VERSION 5.8 ;
BUSBITCHARS "[]" ;
DIVIDERCHAR "/" ;
UNITS
    DATABASE MICRONS 1000 ;
END UNITS

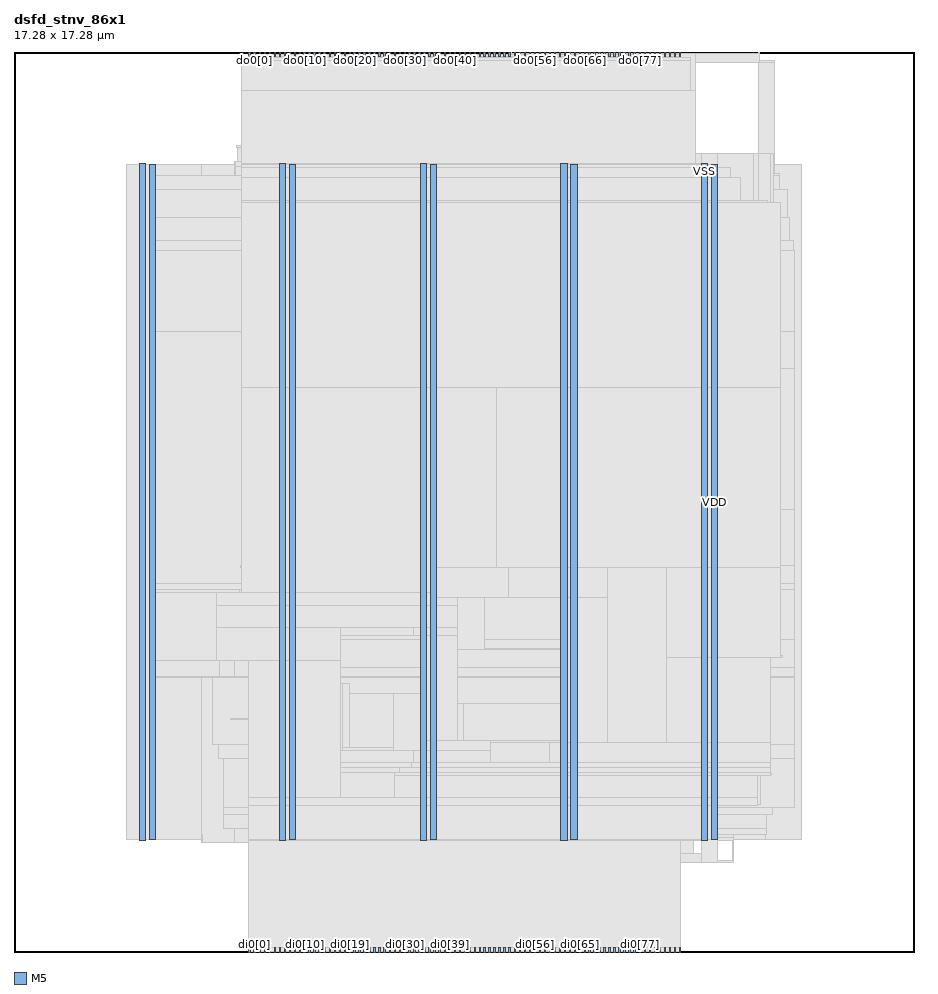
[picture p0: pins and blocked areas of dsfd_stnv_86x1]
MACRO dsfd_stnv_86x1
  FOREIGN dsfd_stnv_86x1 0 0 ;
  CLASS BLOCK ;
  SIZE 17.28 BY 17.28 ;
  PIN di0[0]
    DIRECTION INPUT ;
    USE SIGNAL ;
    PORT
      LAYER M5 ;
        RECT  4.608 0 4.632 0.084 ;
    END
  END di0[0]
  PIN di0[10]
    DIRECTION INPUT ;
    USE SIGNAL ;
    PORT
      LAYER M5 ;
        RECT  5.568 0 5.592 0.084 ;
    END
  END di0[10]
  PIN di0[11]
    DIRECTION INPUT ;
    USE SIGNAL ;
    PORT
      LAYER M5 ;
        RECT  5.664 0 5.688 0.084 ;
    END
  END di0[11]
  PIN di0[12]
    DIRECTION INPUT ;
    USE SIGNAL ;
    PORT
      LAYER M5 ;
        RECT  5.76 0 5.784 0.084 ;
    END
  END di0[12]
  PIN di0[13]
    DIRECTION INPUT ;
    USE SIGNAL ;
    PORT
      LAYER M5 ;
        RECT  5.856 0 5.88 0.084 ;
    END
  END di0[13]
  PIN di0[14]
    DIRECTION INPUT ;
    USE SIGNAL ;
    PORT
      LAYER M5 ;
        RECT  5.952 0 5.976 0.084 ;
    END
  END di0[14]
  PIN di0[15]
    DIRECTION INPUT ;
    USE SIGNAL ;
    PORT
      LAYER M5 ;
        RECT  6.048 0 6.072 0.084 ;
    END
  END di0[15]
  PIN di0[16]
    DIRECTION INPUT ;
    USE SIGNAL ;
    PORT
      LAYER M5 ;
        RECT  6.144 0 6.168 0.084 ;
    END
  END di0[16]
  PIN di0[17]
    DIRECTION INPUT ;
    USE SIGNAL ;
    PORT
      LAYER M5 ;
        RECT  6.24 0 6.264 0.084 ;
    END
  END di0[17]
  PIN di0[18]
    DIRECTION INPUT ;
    USE SIGNAL ;
    PORT
      LAYER M5 ;
        RECT  6.336 0 6.36 0.084 ;
    END
  END di0[18]
  PIN di0[19]
    DIRECTION INPUT ;
    USE SIGNAL ;
    PORT
      LAYER M5 ;
        RECT  6.432 0 6.456 0.084 ;
    END
  END di0[19]
  PIN di0[1]
    DIRECTION INPUT ;
    USE SIGNAL ;
    PORT
      LAYER M5 ;
        RECT  4.704 0 4.728 0.084 ;
    END
  END di0[1]
  PIN di0[20]
    DIRECTION INPUT ;
    USE SIGNAL ;
    PORT
      LAYER M5 ;
        RECT  6.528 0 6.552 0.084 ;
    END
  END di0[20]
  PIN di0[21]
    DIRECTION INPUT ;
    USE SIGNAL ;
    PORT
      LAYER M5 ;
        RECT  6.624 0 6.648 0.084 ;
    END
  END di0[21]
  PIN di0[22]
    DIRECTION INPUT ;
    USE SIGNAL ;
    PORT
      LAYER M5 ;
        RECT  6.72 0 6.744 0.084 ;
    END
  END di0[22]
  PIN di0[23]
    DIRECTION INPUT ;
    USE SIGNAL ;
    PORT
      LAYER M5 ;
        RECT  6.816 0 6.84 0.084 ;
    END
  END di0[23]
  PIN di0[24]
    DIRECTION INPUT ;
    USE SIGNAL ;
    PORT
      LAYER M5 ;
        RECT  6.912 0 6.936 0.084 ;
    END
  END di0[24]
  PIN di0[25]
    DIRECTION INPUT ;
    USE SIGNAL ;
    PORT
      LAYER M5 ;
        RECT  7.008 0 7.032 0.084 ;
    END
  END di0[25]
  PIN di0[26]
    DIRECTION INPUT ;
    USE SIGNAL ;
    PORT
      LAYER M5 ;
        RECT  7.104 0 7.128 0.084 ;
    END
  END di0[26]
  PIN di0[27]
    DIRECTION INPUT ;
    USE SIGNAL ;
    PORT
      LAYER M5 ;
        RECT  7.2 0 7.224 0.084 ;
    END
  END di0[27]
  PIN di0[28]
    DIRECTION INPUT ;
    USE SIGNAL ;
    PORT
      LAYER M5 ;
        RECT  7.296 0 7.32 0.084 ;
    END
  END di0[28]
  PIN di0[29]
    DIRECTION INPUT ;
    USE SIGNAL ;
    PORT
      LAYER M5 ;
        RECT  7.392 0 7.416 0.084 ;
    END
  END di0[29]
  PIN di0[2]
    DIRECTION INPUT ;
    USE SIGNAL ;
    PORT
      LAYER M5 ;
        RECT  4.8 0 4.824 0.084 ;
    END
  END di0[2]
  PIN di0[30]
    DIRECTION INPUT ;
    USE SIGNAL ;
    PORT
      LAYER M5 ;
        RECT  7.488 0 7.512 0.084 ;
    END
  END di0[30]
  PIN di0[31]
    DIRECTION INPUT ;
    USE SIGNAL ;
    PORT
      LAYER M5 ;
        RECT  7.584 0 7.608 0.084 ;
    END
  END di0[31]
  PIN di0[32]
    DIRECTION INPUT ;
    USE SIGNAL ;
    PORT
      LAYER M5 ;
        RECT  7.68 0 7.704 0.084 ;
    END
  END di0[32]
  PIN di0[33]
    DIRECTION INPUT ;
    USE SIGNAL ;
    PORT
      LAYER M5 ;
        RECT  7.776 0 7.8 0.084 ;
    END
  END di0[33]
  PIN di0[34]
    DIRECTION INPUT ;
    USE SIGNAL ;
    PORT
      LAYER M5 ;
        RECT  7.872 0 7.896 0.084 ;
    END
  END di0[34]
  PIN di0[35]
    DIRECTION INPUT ;
    USE SIGNAL ;
    PORT
      LAYER M5 ;
        RECT  7.968 0 7.992 0.084 ;
    END
  END di0[35]
  PIN di0[36]
    DIRECTION INPUT ;
    USE SIGNAL ;
    PORT
      LAYER M5 ;
        RECT  8.064 0 8.088 0.084 ;
    END
  END di0[36]
  PIN di0[37]
    DIRECTION INPUT ;
    USE SIGNAL ;
    PORT
      LAYER M5 ;
        RECT  8.16 0 8.184 0.084 ;
    END
  END di0[37]
  PIN di0[38]
    DIRECTION INPUT ;
    USE SIGNAL ;
    PORT
      LAYER M5 ;
        RECT  8.256 0 8.28 0.084 ;
    END
  END di0[38]
  PIN di0[39]
    DIRECTION INPUT ;
    USE SIGNAL ;
    PORT
      LAYER M5 ;
        RECT  8.352 0 8.376 0.084 ;
    END
  END di0[39]
  PIN di0[3]
    DIRECTION INPUT ;
    USE SIGNAL ;
    PORT
      LAYER M5 ;
        RECT  4.896 0 4.92 0.084 ;
    END
  END di0[3]
  PIN di0[40]
    DIRECTION INPUT ;
    USE SIGNAL ;
    PORT
      LAYER M5 ;
        RECT  8.448 0 8.472 0.084 ;
    END
  END di0[40]
  PIN di0[41]
    DIRECTION INPUT ;
    USE SIGNAL ;
    PORT
      LAYER M5 ;
        RECT  8.544 0 8.568 0.084 ;
    END
  END di0[41]
  PIN di0[42]
    DIRECTION INPUT ;
    USE SIGNAL ;
    PORT
      LAYER M5 ;
        RECT  8.64 0 8.664 0.084 ;
    END
  END di0[42]
  PIN di0[43]
    DIRECTION INPUT ;
    USE SIGNAL ;
    PORT
      LAYER M5 ;
        RECT  8.736 0 8.76 0.084 ;
    END
  END di0[43]
  PIN di0[44]
    DIRECTION INPUT ;
    USE SIGNAL ;
    PORT
      LAYER M5 ;
        RECT  8.832 0 8.856 0.084 ;
    END
  END di0[44]
  PIN di0[45]
    DIRECTION INPUT ;
    USE SIGNAL ;
    PORT
      LAYER M5 ;
        RECT  8.928 0 8.952 0.084 ;
    END
  END di0[45]
  PIN di0[46]
    DIRECTION INPUT ;
    USE SIGNAL ;
    PORT
      LAYER M5 ;
        RECT  9.024 0 9.048 0.084 ;
    END
  END di0[46]
  PIN di0[47]
    DIRECTION INPUT ;
    USE SIGNAL ;
    PORT
      LAYER M5 ;
        RECT  9.12 0 9.144 0.084 ;
    END
  END di0[47]
  PIN di0[48]
    DIRECTION INPUT ;
    USE SIGNAL ;
    PORT
      LAYER M5 ;
        RECT  9.216 0 9.24 0.084 ;
    END
  END di0[48]
  PIN di0[49]
    DIRECTION INPUT ;
    USE SIGNAL ;
    PORT
      LAYER M5 ;
        RECT  9.312 0 9.336 0.084 ;
    END
  END di0[49]
  PIN di0[4]
    DIRECTION INPUT ;
    USE SIGNAL ;
    PORT
      LAYER M5 ;
        RECT  4.992 0 5.016 0.084 ;
    END
  END di0[4]
  PIN di0[50]
    DIRECTION INPUT ;
    USE SIGNAL ;
    PORT
      LAYER M5 ;
        RECT  9.408 0 9.432 0.084 ;
    END
  END di0[50]
  PIN di0[51]
    DIRECTION INPUT ;
    USE SIGNAL ;
    PORT
      LAYER M5 ;
        RECT  9.504 0 9.528 0.084 ;
    END
  END di0[51]
  PIN di0[52]
    DIRECTION INPUT ;
    USE SIGNAL ;
    PORT
      LAYER M5 ;
        RECT  9.6 0 9.624 0.084 ;
    END
  END di0[52]
  PIN di0[53]
    DIRECTION INPUT ;
    USE SIGNAL ;
    PORT
      LAYER M5 ;
        RECT  9.696 0 9.72 0.084 ;
    END
  END di0[53]
  PIN di0[54]
    DIRECTION INPUT ;
    USE SIGNAL ;
    PORT
      LAYER M5 ;
        RECT  9.792 0 9.816 0.084 ;
    END
  END di0[54]
  PIN di0[55]
    DIRECTION INPUT ;
    USE SIGNAL ;
    PORT
      LAYER M5 ;
        RECT  9.888 0 9.912 0.084 ;
    END
  END di0[55]
  PIN di0[56]
    DIRECTION INPUT ;
    USE SIGNAL ;
    PORT
      LAYER M5 ;
        RECT  9.984 0 10.008 0.084 ;
    END
  END di0[56]
  PIN di0[57]
    DIRECTION INPUT ;
    USE SIGNAL ;
    PORT
      LAYER M5 ;
        RECT  10.08 0 10.104 0.084 ;
    END
  END di0[57]
  PIN di0[58]
    DIRECTION INPUT ;
    USE SIGNAL ;
    PORT
      LAYER M5 ;
        RECT  10.176 0 10.2 0.084 ;
    END
  END di0[58]
  PIN di0[59]
    DIRECTION INPUT ;
    USE SIGNAL ;
    PORT
      LAYER M5 ;
        RECT  10.272 0 10.296 0.084 ;
    END
  END di0[59]
  PIN di0[5]
    DIRECTION INPUT ;
    USE SIGNAL ;
    PORT
      LAYER M5 ;
        RECT  5.088 0 5.112 0.084 ;
    END
  END di0[5]
  PIN di0[60]
    DIRECTION INPUT ;
    USE SIGNAL ;
    PORT
      LAYER M5 ;
        RECT  10.368 0 10.392 0.084 ;
    END
  END di0[60]
  PIN di0[61]
    DIRECTION INPUT ;
    USE SIGNAL ;
    PORT
      LAYER M5 ;
        RECT  10.464 0 10.488 0.084 ;
    END
  END di0[61]
  PIN di0[62]
    DIRECTION INPUT ;
    USE SIGNAL ;
    PORT
      LAYER M5 ;
        RECT  10.56 0 10.584 0.084 ;
    END
  END di0[62]
  PIN di0[63]
    DIRECTION INPUT ;
    USE SIGNAL ;
    PORT
      LAYER M5 ;
        RECT  10.656 0 10.68 0.084 ;
    END
  END di0[63]
  PIN di0[64]
    DIRECTION INPUT ;
    USE SIGNAL ;
    PORT
      LAYER M5 ;
        RECT  10.752 0 10.776 0.084 ;
    END
  END di0[64]
  PIN di0[65]
    DIRECTION INPUT ;
    USE SIGNAL ;
    PORT
      LAYER M5 ;
        RECT  10.848 0 10.872 0.084 ;
    END
  END di0[65]
  PIN di0[66]
    DIRECTION INPUT ;
    USE SIGNAL ;
    PORT
      LAYER M5 ;
        RECT  10.944 0 10.968 0.084 ;
    END
  END di0[66]
  PIN di0[67]
    DIRECTION INPUT ;
    USE SIGNAL ;
    PORT
      LAYER M5 ;
        RECT  11.04 0 11.064 0.084 ;
    END
  END di0[67]
  PIN di0[68]
    DIRECTION INPUT ;
    USE SIGNAL ;
    PORT
      LAYER M5 ;
        RECT  11.136 0 11.16 0.084 ;
    END
  END di0[68]
  PIN di0[69]
    DIRECTION INPUT ;
    USE SIGNAL ;
    PORT
      LAYER M5 ;
        RECT  11.232 0 11.256 0.084 ;
    END
  END di0[69]
  PIN di0[6]
    DIRECTION INPUT ;
    USE SIGNAL ;
    PORT
      LAYER M5 ;
        RECT  5.184 0 5.208 0.084 ;
    END
  END di0[6]
  PIN di0[70]
    DIRECTION INPUT ;
    USE SIGNAL ;
    PORT
      LAYER M5 ;
        RECT  11.328 0 11.352 0.084 ;
    END
  END di0[70]
  PIN di0[71]
    DIRECTION INPUT ;
    USE SIGNAL ;
    PORT
      LAYER M5 ;
        RECT  11.424 0 11.448 0.084 ;
    END
  END di0[71]
  PIN di0[72]
    DIRECTION INPUT ;
    USE SIGNAL ;
    PORT
      LAYER M5 ;
        RECT  11.52 0 11.544 0.084 ;
    END
  END di0[72]
  PIN di0[73]
    DIRECTION INPUT ;
    USE SIGNAL ;
    PORT
      LAYER M5 ;
        RECT  11.616 0 11.64 0.084 ;
    END
  END di0[73]
  PIN di0[74]
    DIRECTION INPUT ;
    USE SIGNAL ;
    PORT
      LAYER M5 ;
        RECT  11.712 0 11.736 0.084 ;
    END
  END di0[74]
  PIN di0[75]
    DIRECTION INPUT ;
    USE SIGNAL ;
    PORT
      LAYER M5 ;
        RECT  11.808 0 11.832 0.084 ;
    END
  END di0[75]
  PIN di0[76]
    DIRECTION INPUT ;
    USE SIGNAL ;
    PORT
      LAYER M5 ;
        RECT  11.904 0 11.928 0.084 ;
    END
  END di0[76]
  PIN di0[77]
    DIRECTION INPUT ;
    USE SIGNAL ;
    PORT
      LAYER M5 ;
        RECT  12 0 12.024 0.084 ;
    END
  END di0[77]
  PIN di0[78]
    DIRECTION INPUT ;
    USE SIGNAL ;
    PORT
      LAYER M5 ;
        RECT  12.096 0 12.12 0.084 ;
    END
  END di0[78]
  PIN di0[79]
    DIRECTION INPUT ;
    USE SIGNAL ;
    PORT
      LAYER M5 ;
        RECT  12.192 0 12.216 0.084 ;
    END
  END di0[79]
  PIN di0[7]
    DIRECTION INPUT ;
    USE SIGNAL ;
    PORT
      LAYER M5 ;
        RECT  5.28 0 5.304 0.084 ;
    END
  END di0[7]
  PIN di0[80]
    DIRECTION INPUT ;
    USE SIGNAL ;
    PORT
      LAYER M5 ;
        RECT  12.288 0 12.312 0.084 ;
    END
  END di0[80]
  PIN di0[81]
    DIRECTION INPUT ;
    USE SIGNAL ;
    PORT
      LAYER M5 ;
        RECT  12.384 0 12.408 0.084 ;
    END
  END di0[81]
  PIN di0[82]
    DIRECTION INPUT ;
    USE SIGNAL ;
    PORT
      LAYER M5 ;
        RECT  12.48 0 12.504 0.084 ;
    END
  END di0[82]
  PIN di0[83]
    DIRECTION INPUT ;
    USE SIGNAL ;
    PORT
      LAYER M5 ;
        RECT  12.576 0 12.6 0.084 ;
    END
  END di0[83]
  PIN di0[84]
    DIRECTION INPUT ;
    USE SIGNAL ;
    PORT
      LAYER M5 ;
        RECT  12.672 0 12.696 0.084 ;
    END
  END di0[84]
  PIN di0[85]
    DIRECTION INPUT ;
    USE SIGNAL ;
    PORT
      LAYER M5 ;
        RECT  12.768 0 12.792 0.084 ;
    END
  END di0[85]
  PIN di0[8]
    DIRECTION INPUT ;
    USE SIGNAL ;
    PORT
      LAYER M5 ;
        RECT  5.376 0 5.4 0.084 ;
    END
  END di0[8]
  PIN di0[9]
    DIRECTION INPUT ;
    USE SIGNAL ;
    PORT
      LAYER M5 ;
        RECT  5.472 0 5.496 0.084 ;
    END
  END di0[9]
  PIN do0[0]
    DIRECTION OUTPUT ;
    USE SIGNAL ;
    PORT
      LAYER M5 ;
        RECT  4.608 17.196 4.632 17.28 ;
    END
  END do0[0]
  PIN do0[10]
    DIRECTION OUTPUT ;
    USE SIGNAL ;
    PORT
      LAYER M5 ;
        RECT  5.568 17.196 5.592 17.28 ;
    END
  END do0[10]
  PIN do0[11]
    DIRECTION OUTPUT ;
    USE SIGNAL ;
    PORT
      LAYER M5 ;
        RECT  5.664 17.196 5.688 17.28 ;
    END
  END do0[11]
  PIN do0[12]
    DIRECTION OUTPUT ;
    USE SIGNAL ;
    PORT
      LAYER M5 ;
        RECT  5.76 17.196 5.784 17.28 ;
    END
  END do0[12]
  PIN do0[13]
    DIRECTION OUTPUT ;
    USE SIGNAL ;
    PORT
      LAYER M5 ;
        RECT  5.856 17.196 5.88 17.28 ;
    END
  END do0[13]
  PIN do0[14]
    DIRECTION OUTPUT ;
    USE SIGNAL ;
    PORT
      LAYER M5 ;
        RECT  5.952 17.196 5.976 17.28 ;
    END
  END do0[14]
  PIN do0[15]
    DIRECTION OUTPUT ;
    USE SIGNAL ;
    PORT
      LAYER M5 ;
        RECT  6.048 17.196 6.072 17.28 ;
    END
  END do0[15]
  PIN do0[16]
    DIRECTION OUTPUT ;
    USE SIGNAL ;
    PORT
      LAYER M5 ;
        RECT  6.144 17.196 6.168 17.28 ;
    END
  END do0[16]
  PIN do0[17]
    DIRECTION OUTPUT ;
    USE SIGNAL ;
    PORT
      LAYER M5 ;
        RECT  6.24 17.196 6.264 17.28 ;
    END
  END do0[17]
  PIN do0[18]
    DIRECTION OUTPUT ;
    USE SIGNAL ;
    PORT
      LAYER M5 ;
        RECT  6.336 17.196 6.36 17.28 ;
    END
  END do0[18]
  PIN do0[19]
    DIRECTION OUTPUT ;
    USE SIGNAL ;
    PORT
      LAYER M5 ;
        RECT  6.432 17.196 6.456 17.28 ;
    END
  END do0[19]
  PIN do0[1]
    DIRECTION OUTPUT ;
    USE SIGNAL ;
    PORT
      LAYER M5 ;
        RECT  4.704 17.196 4.728 17.28 ;
    END
  END do0[1]
  PIN do0[20]
    DIRECTION OUTPUT ;
    USE SIGNAL ;
    PORT
      LAYER M5 ;
        RECT  6.528 17.196 6.552 17.28 ;
    END
  END do0[20]
  PIN do0[21]
    DIRECTION OUTPUT ;
    USE SIGNAL ;
    PORT
      LAYER M5 ;
        RECT  6.624 17.196 6.648 17.28 ;
    END
  END do0[21]
  PIN do0[22]
    DIRECTION OUTPUT ;
    USE SIGNAL ;
    PORT
      LAYER M5 ;
        RECT  6.72 17.196 6.744 17.28 ;
    END
  END do0[22]
  PIN do0[23]
    DIRECTION OUTPUT ;
    USE SIGNAL ;
    PORT
      LAYER M5 ;
        RECT  6.816 17.196 6.84 17.28 ;
    END
  END do0[23]
  PIN do0[24]
    DIRECTION OUTPUT ;
    USE SIGNAL ;
    PORT
      LAYER M5 ;
        RECT  6.912 17.196 6.936 17.28 ;
    END
  END do0[24]
  PIN do0[25]
    DIRECTION OUTPUT ;
    USE SIGNAL ;
    PORT
      LAYER M5 ;
        RECT  7.008 17.196 7.032 17.28 ;
    END
  END do0[25]
  PIN do0[26]
    DIRECTION OUTPUT ;
    USE SIGNAL ;
    PORT
      LAYER M5 ;
        RECT  7.104 17.196 7.128 17.28 ;
    END
  END do0[26]
  PIN do0[27]
    DIRECTION OUTPUT ;
    USE SIGNAL ;
    PORT
      LAYER M5 ;
        RECT  7.2 17.196 7.224 17.28 ;
    END
  END do0[27]
  PIN do0[28]
    DIRECTION OUTPUT ;
    USE SIGNAL ;
    PORT
      LAYER M5 ;
        RECT  7.296 17.196 7.32 17.28 ;
    END
  END do0[28]
  PIN do0[29]
    DIRECTION OUTPUT ;
    USE SIGNAL ;
    PORT
      LAYER M5 ;
        RECT  7.392 17.196 7.416 17.28 ;
    END
  END do0[29]
  PIN do0[2]
    DIRECTION OUTPUT ;
    USE SIGNAL ;
    PORT
      LAYER M5 ;
        RECT  4.8 17.196 4.824 17.28 ;
    END
  END do0[2]
  PIN do0[30]
    DIRECTION OUTPUT ;
    USE SIGNAL ;
    PORT
      LAYER M5 ;
        RECT  7.488 17.196 7.512 17.28 ;
    END
  END do0[30]
  PIN do0[31]
    DIRECTION OUTPUT ;
    USE SIGNAL ;
    PORT
      LAYER M5 ;
        RECT  7.584 17.196 7.608 17.28 ;
    END
  END do0[31]
  PIN do0[32]
    DIRECTION OUTPUT ;
    USE SIGNAL ;
    PORT
      LAYER M5 ;
        RECT  7.68 17.196 7.704 17.28 ;
    END
  END do0[32]
  PIN do0[33]
    DIRECTION OUTPUT ;
    USE SIGNAL ;
    PORT
      LAYER M5 ;
        RECT  7.776 17.196 7.8 17.28 ;
    END
  END do0[33]
  PIN do0[34]
    DIRECTION OUTPUT ;
    USE SIGNAL ;
    PORT
      LAYER M5 ;
        RECT  7.872 17.196 7.896 17.28 ;
    END
  END do0[34]
  PIN do0[35]
    DIRECTION OUTPUT ;
    USE SIGNAL ;
    PORT
      LAYER M5 ;
        RECT  7.968 17.196 7.992 17.28 ;
    END
  END do0[35]
  PIN do0[36]
    DIRECTION OUTPUT ;
    USE SIGNAL ;
    PORT
      LAYER M5 ;
        RECT  8.064 17.196 8.088 17.28 ;
    END
  END do0[36]
  PIN do0[37]
    DIRECTION OUTPUT ;
    USE SIGNAL ;
    PORT
      LAYER M5 ;
        RECT  8.16 17.196 8.184 17.28 ;
    END
  END do0[37]
  PIN do0[38]
    DIRECTION OUTPUT ;
    USE SIGNAL ;
    PORT
      LAYER M5 ;
        RECT  8.256 17.196 8.28 17.28 ;
    END
  END do0[38]
  PIN do0[39]
    DIRECTION OUTPUT ;
    USE SIGNAL ;
    PORT
      LAYER M5 ;
        RECT  8.352 17.196 8.376 17.28 ;
    END
  END do0[39]
  PIN do0[3]
    DIRECTION OUTPUT ;
    USE SIGNAL ;
    PORT
      LAYER M5 ;
        RECT  4.896 17.196 4.92 17.28 ;
    END
  END do0[3]
  PIN do0[40]
    DIRECTION OUTPUT ;
    USE SIGNAL ;
    PORT
      LAYER M5 ;
        RECT  8.448 17.196 8.472 17.28 ;
    END
  END do0[40]
  PIN do0[41]
    DIRECTION OUTPUT ;
    USE SIGNAL ;
    PORT
      LAYER M5 ;
        RECT  8.544 17.196 8.568 17.28 ;
    END
  END do0[41]
  PIN do0[42]
    DIRECTION OUTPUT ;
    USE SIGNAL ;
    PORT
      LAYER M5 ;
        RECT  8.64 17.196 8.664 17.28 ;
    END
  END do0[42]
  PIN do0[43]
    DIRECTION OUTPUT ;
    USE SIGNAL ;
    PORT
      LAYER M5 ;
        RECT  8.736 17.196 8.76 17.28 ;
    END
  END do0[43]
  PIN do0[44]
    DIRECTION OUTPUT ;
    USE SIGNAL ;
    PORT
      LAYER M5 ;
        RECT  8.832 17.196 8.856 17.28 ;
    END
  END do0[44]
  PIN do0[45]
    DIRECTION OUTPUT ;
    USE SIGNAL ;
    PORT
      LAYER M5 ;
        RECT  8.928 17.196 8.952 17.28 ;
    END
  END do0[45]
  PIN do0[46]
    DIRECTION OUTPUT ;
    USE SIGNAL ;
    PORT
      LAYER M5 ;
        RECT  9.024 17.196 9.048 17.28 ;
    END
  END do0[46]
  PIN do0[47]
    DIRECTION OUTPUT ;
    USE SIGNAL ;
    PORT
      LAYER M5 ;
        RECT  9.12 17.196 9.144 17.28 ;
    END
  END do0[47]
  PIN do0[48]
    DIRECTION OUTPUT ;
    USE SIGNAL ;
    PORT
      LAYER M5 ;
        RECT  9.216 17.196 9.24 17.28 ;
    END
  END do0[48]
  PIN do0[49]
    DIRECTION OUTPUT ;
    USE SIGNAL ;
    PORT
      LAYER M5 ;
        RECT  9.312 17.196 9.336 17.28 ;
    END
  END do0[49]
  PIN do0[4]
    DIRECTION OUTPUT ;
    USE SIGNAL ;
    PORT
      LAYER M5 ;
        RECT  4.992 17.196 5.016 17.28 ;
    END
  END do0[4]
  PIN do0[50]
    DIRECTION OUTPUT ;
    USE SIGNAL ;
    PORT
      LAYER M5 ;
        RECT  9.408 17.196 9.432 17.28 ;
    END
  END do0[50]
  PIN do0[51]
    DIRECTION OUTPUT ;
    USE SIGNAL ;
    PORT
      LAYER M5 ;
        RECT  9.504 17.196 9.528 17.28 ;
    END
  END do0[51]
  PIN do0[52]
    DIRECTION OUTPUT ;
    USE SIGNAL ;
    PORT
      LAYER M5 ;
        RECT  9.6 17.196 9.624 17.28 ;
    END
  END do0[52]
  PIN do0[53]
    DIRECTION OUTPUT ;
    USE SIGNAL ;
    PORT
      LAYER M5 ;
        RECT  9.696 17.196 9.72 17.28 ;
    END
  END do0[53]
  PIN do0[54]
    DIRECTION OUTPUT ;
    USE SIGNAL ;
    PORT
      LAYER M5 ;
        RECT  9.792 17.196 9.816 17.28 ;
    END
  END do0[54]
  PIN do0[55]
    DIRECTION OUTPUT ;
    USE SIGNAL ;
    PORT
      LAYER M5 ;
        RECT  9.888 17.196 9.912 17.28 ;
    END
  END do0[55]
  PIN do0[56]
    DIRECTION OUTPUT ;
    USE SIGNAL ;
    PORT
      LAYER M5 ;
        RECT  9.984 17.196 10.008 17.28 ;
    END
  END do0[56]
  PIN do0[57]
    DIRECTION OUTPUT ;
    USE SIGNAL ;
    PORT
      LAYER M5 ;
        RECT  10.08 17.196 10.104 17.28 ;
    END
  END do0[57]
  PIN do0[58]
    DIRECTION OUTPUT ;
    USE SIGNAL ;
    PORT
      LAYER M5 ;
        RECT  10.176 17.196 10.2 17.28 ;
    END
  END do0[58]
  PIN do0[59]
    DIRECTION OUTPUT ;
    USE SIGNAL ;
    PORT
      LAYER M5 ;
        RECT  10.272 17.196 10.296 17.28 ;
    END
  END do0[59]
  PIN do0[5]
    DIRECTION OUTPUT ;
    USE SIGNAL ;
    PORT
      LAYER M5 ;
        RECT  5.088 17.196 5.112 17.28 ;
    END
  END do0[5]
  PIN do0[60]
    DIRECTION OUTPUT ;
    USE SIGNAL ;
    PORT
      LAYER M5 ;
        RECT  10.368 17.196 10.392 17.28 ;
    END
  END do0[60]
  PIN do0[61]
    DIRECTION OUTPUT ;
    USE SIGNAL ;
    PORT
      LAYER M5 ;
        RECT  10.464 17.196 10.488 17.28 ;
    END
  END do0[61]
  PIN do0[62]
    DIRECTION OUTPUT ;
    USE SIGNAL ;
    PORT
      LAYER M5 ;
        RECT  10.56 17.196 10.584 17.28 ;
    END
  END do0[62]
  PIN do0[63]
    DIRECTION OUTPUT ;
    USE SIGNAL ;
    PORT
      LAYER M5 ;
        RECT  10.656 17.196 10.68 17.28 ;
    END
  END do0[63]
  PIN do0[64]
    DIRECTION OUTPUT ;
    USE SIGNAL ;
    PORT
      LAYER M5 ;
        RECT  10.752 17.196 10.776 17.28 ;
    END
  END do0[64]
  PIN do0[65]
    DIRECTION OUTPUT ;
    USE SIGNAL ;
    PORT
      LAYER M5 ;
        RECT  10.848 17.196 10.872 17.28 ;
    END
  END do0[65]
  PIN do0[66]
    DIRECTION OUTPUT ;
    USE SIGNAL ;
    PORT
      LAYER M5 ;
        RECT  10.944 17.196 10.968 17.28 ;
    END
  END do0[66]
  PIN do0[67]
    DIRECTION OUTPUT ;
    USE SIGNAL ;
    PORT
      LAYER M5 ;
        RECT  11.04 17.196 11.064 17.28 ;
    END
  END do0[67]
  PIN do0[68]
    DIRECTION OUTPUT ;
    USE SIGNAL ;
    PORT
      LAYER M5 ;
        RECT  11.136 17.196 11.16 17.28 ;
    END
  END do0[68]
  PIN do0[69]
    DIRECTION OUTPUT ;
    USE SIGNAL ;
    PORT
      LAYER M5 ;
        RECT  11.232 17.196 11.256 17.28 ;
    END
  END do0[69]
  PIN do0[6]
    DIRECTION OUTPUT ;
    USE SIGNAL ;
    PORT
      LAYER M5 ;
        RECT  5.184 17.196 5.208 17.28 ;
    END
  END do0[6]
  PIN do0[70]
    DIRECTION OUTPUT ;
    USE SIGNAL ;
    PORT
      LAYER M5 ;
        RECT  11.328 17.196 11.352 17.28 ;
    END
  END do0[70]
  PIN do0[71]
    DIRECTION OUTPUT ;
    USE SIGNAL ;
    PORT
      LAYER M5 ;
        RECT  11.424 17.196 11.448 17.28 ;
    END
  END do0[71]
  PIN do0[72]
    DIRECTION OUTPUT ;
    USE SIGNAL ;
    PORT
      LAYER M5 ;
        RECT  11.52 17.196 11.544 17.28 ;
    END
  END do0[72]
  PIN do0[73]
    DIRECTION OUTPUT ;
    USE SIGNAL ;
    PORT
      LAYER M5 ;
        RECT  11.616 17.196 11.64 17.28 ;
    END
  END do0[73]
  PIN do0[74]
    DIRECTION OUTPUT ;
    USE SIGNAL ;
    PORT
      LAYER M5 ;
        RECT  11.712 17.196 11.736 17.28 ;
    END
  END do0[74]
  PIN do0[75]
    DIRECTION OUTPUT ;
    USE SIGNAL ;
    PORT
      LAYER M5 ;
        RECT  11.808 17.196 11.832 17.28 ;
    END
  END do0[75]
  PIN do0[76]
    DIRECTION OUTPUT ;
    USE SIGNAL ;
    PORT
      LAYER M5 ;
        RECT  11.904 17.196 11.928 17.28 ;
    END
  END do0[76]
  PIN do0[77]
    DIRECTION OUTPUT ;
    USE SIGNAL ;
    PORT
      LAYER M5 ;
        RECT  12 17.196 12.024 17.28 ;
    END
  END do0[77]
  PIN do0[78]
    DIRECTION OUTPUT ;
    USE SIGNAL ;
    PORT
      LAYER M5 ;
        RECT  12.096 17.196 12.12 17.28 ;
    END
  END do0[78]
  PIN do0[79]
    DIRECTION OUTPUT ;
    USE SIGNAL ;
    PORT
      LAYER M5 ;
        RECT  12.192 17.196 12.216 17.28 ;
    END
  END do0[79]
  PIN do0[7]
    DIRECTION OUTPUT ;
    USE SIGNAL ;
    PORT
      LAYER M5 ;
        RECT  5.28 17.196 5.304 17.28 ;
    END
  END do0[7]
  PIN do0[80]
    DIRECTION OUTPUT ;
    USE SIGNAL ;
    PORT
      LAYER M5 ;
        RECT  12.288 17.196 12.312 17.28 ;
    END
  END do0[80]
  PIN do0[81]
    DIRECTION OUTPUT ;
    USE SIGNAL ;
    PORT
      LAYER M5 ;
        RECT  12.384 17.196 12.408 17.28 ;
    END
  END do0[81]
  PIN do0[82]
    DIRECTION OUTPUT ;
    USE SIGNAL ;
    PORT
      LAYER M5 ;
        RECT  12.48 17.196 12.504 17.28 ;
    END
  END do0[82]
  PIN do0[83]
    DIRECTION OUTPUT ;
    USE SIGNAL ;
    PORT
      LAYER M5 ;
        RECT  12.576 17.196 12.6 17.28 ;
    END
  END do0[83]
  PIN do0[84]
    DIRECTION OUTPUT ;
    USE SIGNAL ;
    PORT
      LAYER M5 ;
        RECT  12.672 17.196 12.696 17.28 ;
    END
  END do0[84]
  PIN do0[85]
    DIRECTION OUTPUT ;
    USE SIGNAL ;
    PORT
      LAYER M5 ;
        RECT  12.768 17.196 12.792 17.28 ;
    END
  END do0[85]
  PIN do0[8]
    DIRECTION OUTPUT ;
    USE SIGNAL ;
    PORT
      LAYER M5 ;
        RECT  5.376 17.196 5.4 17.28 ;
    END
  END do0[8]
  PIN do0[9]
    DIRECTION OUTPUT ;
    USE SIGNAL ;
    PORT
      LAYER M5 ;
        RECT  5.472 17.196 5.496 17.28 ;
    END
  END do0[9]
  PIN fi0[0]
    DIRECTION INPUT ;
    USE SIGNAL ;
    PORT
      LAYER M5 ;
        RECT  4.512 0 4.536 0.084 ;
    END
  END fi0[0]
  PIN fo0[0]
    DIRECTION OUTPUT ;
    USE SIGNAL ;
    PORT
      LAYER M5 ;
        RECT  4.512 17.196 4.536 17.28 ;
    END
  END fo0[0]
  PIN VDD
    DIRECTION INOUT ;
    USE POWER ;
    PORT
      LAYER M5 ;
        RECT  13.392 2.151 13.512 15.129 ;
        RECT  10.692 2.151 10.812 15.129 ;
        RECT  7.992 2.151 8.112 15.129 ;
        RECT  5.292 2.151 5.412 15.129 ;
        RECT  2.592 2.151 2.712 15.129 ;
    END
  END VDD
  PIN VSS
    DIRECTION INOUT ;
    USE GROUND ;
    PORT
      LAYER M5 ;
        RECT  13.2 2.137 13.32 15.143 ;
        RECT  10.5 2.137 10.62 15.143 ;
        RECT  7.8 2.137 7.92 15.143 ;
        RECT  5.1 2.137 5.22 15.143 ;
        RECT  2.4 2.137 2.52 15.143 ;
    END
  END VSS
  # OT_OBS_CLOSED layer=M5 d_um=1.536 added=12
  OBS
    LAYER RVTN ;
     RECT  2.16 2.16 15.12 2.295 ;
     RECT  2.16 2.565 15.12 2.835 ;
     RECT  2.16 3.105 15.12 3.375 ;
     RECT  2.16 3.645 15.12 3.915 ;
     RECT  2.16 4.185 15.12 4.455 ;
     RECT  2.16 4.725 15.12 4.995 ;
     RECT  2.16 5.265 15.12 5.535 ;
     RECT  2.16 5.805 15.12 6.075 ;
     RECT  2.16 6.345 15.12 6.615 ;
     RECT  2.16 6.885 15.12 7.155 ;
     RECT  2.16 7.425 15.12 7.695 ;
     RECT  2.16 7.965 15.12 8.235 ;
     RECT  2.16 8.505 15.12 8.775 ;
     RECT  2.16 9.045 15.12 9.315 ;
     RECT  2.16 9.585 15.12 9.855 ;
     RECT  2.16 10.125 15.12 10.395 ;
     RECT  2.16 10.665 15.12 10.935 ;
     RECT  2.16 11.205 15.12 11.475 ;
     RECT  2.16 11.745 15.12 12.015 ;
     RECT  2.16 12.285 15.12 12.555 ;
     RECT  2.16 12.825 15.12 13.095 ;
     RECT  2.16 13.365 15.12 13.635 ;
     RECT  2.16 13.905 15.12 14.175 ;
     RECT  2.16 14.445 15.12 14.715 ;
     RECT  2.16 14.985 15.12 15.12 ;
    LAYER RVTP ;
     RECT  2.16 2.295 15.12 2.565 ;
     RECT  2.16 2.835 15.12 3.105 ;
     RECT  2.16 3.375 15.12 3.645 ;
     RECT  2.16 3.915 15.12 4.185 ;
     RECT  2.16 4.455 15.12 4.725 ;
     RECT  2.16 4.995 15.12 5.265 ;
     RECT  2.16 5.535 15.12 5.805 ;
     RECT  2.16 6.075 15.12 6.345 ;
     RECT  2.16 6.615 15.12 6.885 ;
     RECT  2.16 7.155 15.12 7.425 ;
     RECT  2.16 7.695 15.12 7.965 ;
     RECT  2.16 8.235 15.12 8.505 ;
     RECT  2.16 8.775 15.12 9.045 ;
     RECT  2.16 9.315 15.12 9.585 ;
     RECT  2.16 9.855 15.12 10.125 ;
     RECT  2.16 10.395 15.12 10.665 ;
     RECT  2.16 10.935 15.12 11.205 ;
     RECT  2.16 11.475 15.12 11.745 ;
     RECT  2.16 12.015 15.12 12.285 ;
     RECT  2.16 12.555 15.12 12.825 ;
     RECT  2.16 13.095 15.12 13.365 ;
     RECT  2.16 13.635 15.12 13.905 ;
     RECT  2.16 14.175 15.12 14.445 ;
     RECT  2.16 14.715 15.12 14.985 ;
    LAYER M1 ;
     RECT  2.16 2.151 15.12 15.129 ;
    LAYER M2 ;
     RECT  2.16 2.151 3.595 15.129 ;
     RECT  3.595 2.106 4.243 15.129 ;
     RECT  4.243 2.106 4.631 15.174 ;
     RECT  4.631 2.151 4.775 15.174 ;
     RECT  4.775 2.151 13.675 15.129 ;
     RECT  13.675 2.151 14.423 15.174 ;
     RECT  14.423 2.151 15.12 15.129 ;
    LAYER M3 ;
     RECT  8.28 0.091 8.298 0.187 ;
     RECT  8.28 0.187 8.442 0.317 ;
     RECT  8.424 0.317 8.442 0.557 ;
     RECT  4.608 0.571 4.626 0.667 ;
     RECT  4.572 0.667 4.626 0.715 ;
     RECT  4.572 0.715 4.662 1.723 ;
     RECT  5.436 0.091 6.102 1.723 ;
     RECT  4.572 1.723 8.874 1.771 ;
     RECT  10.224 1.723 10.35 1.771 ;
     RECT  11.088 1.723 11.538 1.771 ;
     RECT  12.528 1.723 12.546 1.771 ;
     RECT  12.384 1.771 13.05 1.819 ;
     RECT  12.312 1.819 13.05 2.143 ;
     RECT  13.788 1.723 13.806 2.143 ;
     RECT  4.572 1.771 9.09 2.191 ;
     RECT  10.224 1.771 11.538 2.191 ;
     RECT  12.312 2.143 13.806 2.191 ;
     RECT  3.6 2.101 3.618 2.255 ;
     RECT  4.572 2.191 13.806 2.263 ;
     RECT  4.572 2.263 14.454 2.371 ;
     RECT  2.415 2.143 2.505 2.413 ;
     RECT  4.032 2.371 14.454 2.641 ;
     RECT  4.032 2.641 14.562 2.767 ;
     RECT  4.032 2.767 14.994 3.721 ;
     RECT  3.924 3.721 14.994 3.991 ;
     RECT  2.415 2.413 2.697 5.269 ;
     RECT  3.816 3.991 14.994 5.269 ;
     RECT  2.415 5.269 14.994 5.297 ;
     RECT  4.752 5.297 14.994 5.459 ;
     RECT  5.004 5.459 14.994 5.999 ;
     RECT  2.415 5.297 3.942 6.421 ;
     RECT  2.415 6.421 4.338 6.961 ;
     RECT  5.115 5.999 14.994 6.961 ;
     RECT  2.415 6.961 14.994 7.079 ;
     RECT  6.768 7.079 14.994 7.421 ;
     RECT  6.912 7.421 14.994 8.501 ;
     RECT  6.912 8.501 9.126 11.209 ;
     RECT  9.864 8.501 14.994 11.209 ;
     RECT  2.415 7.079 5.994 11.911 ;
     RECT  6.912 11.209 14.994 11.911 ;
     RECT  2.415 11.911 14.994 13.469 ;
     RECT  2.415 13.469 14.958 13.667 ;
     RECT  2.415 13.667 14.886 14.099 ;
     RECT  2.415 14.099 14.85 14.639 ;
     RECT  2.415 14.639 14.706 14.909 ;
     RECT  7.815 14.909 8.298 14.945 ;
     RECT  9.504 14.909 14.706 14.945 ;
     RECT  7.815 14.945 7.974 14.957 ;
     RECT  9.504 14.945 14.598 15.017 ;
     RECT  9.504 15.017 11.178 15.053 ;
     RECT  11.916 15.017 14.598 15.053 ;
     RECT  4.248 14.909 6.714 15.089 ;
     RECT  2.415 14.909 2.505 15.137 ;
     RECT  7.815 14.957 7.905 15.137 ;
     RECT  13.215 15.053 14.598 15.137 ;
     RECT  4.248 15.089 5.49 15.179 ;
     RECT  13.68 15.137 14.598 15.179 ;
     RECT  9.504 15.053 10.674 15.293 ;
     RECT  11.916 15.053 11.97 15.293 ;
     RECT  11.952 15.293 11.97 15.389 ;
     RECT  4.284 15.179 5.49 15.485 ;
     RECT  9.504 15.293 10.494 15.965 ;
     RECT  4.5 15.485 5.49 16.013 ;
     RECT  6.624 15.089 6.678 16.445 ;
     RECT  6.624 16.445 6.642 16.541 ;
     RECT  10.152 15.965 10.494 16.541 ;
     RECT  10.476 16.541 10.494 16.589 ;
     RECT  5.472 16.013 5.49 17.021 ;
     RECT  14.292 15.179 14.598 17.117 ;
     RECT  4.5 16.013 4.518 17.165 ;
     RECT  5.94 17.035 5.958 17.165 ;
     RECT  11.664 17.035 11.682 17.165 ;
     RECT  9.54 17.131 9.558 17.261 ;
     RECT  14.292 17.117 14.31 17.261 ;
    LAYER M4 ;
     RECT  2.408 2.148 2.512 15.132 ;
     RECT  2.512 2.418 2.704 14.862 ;
     RECT  3.836 5.616 3.923 5.64 ;
     RECT  3.877 6.864 3.989 6.888 ;
     RECT  4.357 17.088 4.489 17.112 ;
     RECT  4.273 15.456 4.525 15.48 ;
     RECT  4.525 15.408 4.561 15.48 ;
     RECT  4.561 0.672 4.597 0.696 ;
     RECT  4.561 14.832 4.597 15.48 ;
     RECT  4.597 0.576 4.633 0.696 ;
     RECT  4.489 17.088 4.643 17.16 ;
     RECT  4.597 14.688 4.705 15.48 ;
     RECT  4.165 4.464 4.741 4.488 ;
     RECT  4.597 2.208 4.777 2.232 ;
     RECT  4.705 14.256 4.849 15.48 ;
     RECT  4.501 6.336 4.933 6.36 ;
     RECT  4.633 0.576 4.981 0.744 ;
     RECT  4.777 1.728 4.981 2.232 ;
     RECT  4.849 14.256 4.981 16.008 ;
     RECT  4.981 0.576 5.108 2.904 ;
     RECT  4.741 4.368 5.108 4.488 ;
     RECT  4.933 6 5.108 6.36 ;
     RECT  4.345 7.392 5.108 7.416 ;
     RECT  4.981 13.632 5.108 16.008 ;
     RECT  5.108 0.576 5.123 16.008 ;
     RECT  5.123 1.104 5.404 16.008 ;
     RECT  5.404 12.528 5.411 16.008 ;
     RECT  4.643 17.088 5.461 17.112 ;
     RECT  5.404 1.104 5.603 1.848 ;
     RECT  5.404 3.408 5.651 6.84 ;
     RECT  5.411 12.528 5.699 15.432 ;
     RECT  5.603 1.104 5.795 1.8 ;
     RECT  5.461 16.992 5.89 17.112 ;
     RECT  5.89 16.992 6.083 17.16 ;
     RECT  5.269 0.096 6.124 0.12 ;
     RECT  6.083 16.992 6.131 17.064 ;
     RECT  5.651 3.408 6.275 5.352 ;
     RECT  6.275 3.408 6.301 5.16 ;
     RECT  5.651 6.336 6.421 6.84 ;
     RECT  5.404 7.92 6.421 7.944 ;
     RECT  6.301 3.936 6.437 5.16 ;
     RECT  6.421 16.512 6.517 16.536 ;
     RECT  6.421 6.336 6.613 7.944 ;
     RECT  6.517 16.416 6.689 16.536 ;
     RECT  5.699 12.528 6.709 14.856 ;
     RECT  5.795 1.728 6.997 1.8 ;
     RECT  6.709 11.904 7.225 14.856 ;
     RECT  6.517 2.88 7.285 2.952 ;
     RECT  6.437 3.936 7.285 4.968 ;
     RECT  6.613 6.24 7.669 7.944 ;
     RECT  7.225 11.376 7.669 14.856 ;
     RECT  6.997 1.728 7.808 1.896 ;
     RECT  7.285 2.88 7.808 4.968 ;
     RECT  7.669 6.096 7.808 7.944 ;
     RECT  7.669 11.232 7.808 14.952 ;
     RECT  7.808 1.728 7.912 15.132 ;
     RECT  7.333 16.944 7.957 17.112 ;
     RECT  7.912 1.728 7.985 14.952 ;
     RECT  7.957 16.512 8.053 17.112 ;
     RECT  7.985 1.728 8.104 14.862 ;
     RECT  7.621 0.144 8.149 0.168 ;
     RECT  8.149 0.144 8.242 0.456 ;
     RECT  8.242 0.096 8.293 0.456 ;
     RECT  8.293 0.096 8.387 0.552 ;
     RECT  8.387 0.192 8.453 0.552 ;
     RECT  8.453 0.192 8.483 0.312 ;
     RECT  8.483 0.192 8.497 0.216 ;
     RECT  8.104 10.848 8.572 14.856 ;
     RECT  8.053 15.936 8.627 17.112 ;
     RECT  8.104 2.832 8.633 4.776 ;
     RECT  8.104 1.728 9.001 1.848 ;
     RECT  8.104 5.808 9.029 6.888 ;
     RECT  9.029 6.816 9.097 6.888 ;
     RECT  9.001 1.728 9.101 1.8 ;
     RECT  9.097 6.816 9.233 7.128 ;
     RECT  9.233 6.816 9.341 7.416 ;
     RECT  9.341 6.816 9.425 7.992 ;
     RECT  8.572 11.232 9.445 14.856 ;
     RECT  8.627 16.944 9.485 17.112 ;
     RECT  9.485 16.944 9.529 17.16 ;
     RECT  8.627 15.936 9.533 15.96 ;
     RECT  9.529 16.944 9.877 17.256 ;
     RECT  9.101 1.728 10.252 1.752 ;
     RECT  10.252 1.728 10.261 1.8 ;
     RECT  9.445 11.232 10.261 14.904 ;
     RECT  10.261 1.728 10.508 1.896 ;
     RECT  8.633 2.88 10.508 4.776 ;
     RECT  9.029 5.808 10.508 5.832 ;
     RECT  9.425 6.816 10.508 7.416 ;
     RECT  10.261 11.232 10.508 15.384 ;
     RECT  10.309 0.144 10.595 0.168 ;
     RECT  10.508 1.728 10.804 15.384 ;
     RECT  10.804 1.728 10.865 5.352 ;
     RECT  10.865 2.88 11.189 5.352 ;
     RECT  10.804 8.496 11.449 8.52 ;
     RECT  10.804 9.696 11.699 9.72 ;
     RECT  10.804 6.768 11.809 7.416 ;
     RECT  10.804 10.896 11.981 15.384 ;
     RECT  11.189 5.328 12.049 5.352 ;
     RECT  11.809 6.768 12.049 7.128 ;
     RECT  12.049 5.328 12.089 7.128 ;
     RECT  10.865 1.728 12.257 1.8 ;
     RECT  12.257 1.728 12.34 1.848 ;
     RECT  12.089 6.816 12.805 7.128 ;
     RECT  11.189 2.88 13.052 4.344 ;
     RECT  12.089 5.808 13.052 5.832 ;
     RECT  9.877 16.512 13.091 17.256 ;
     RECT  12.34 1.728 13.208 1.896 ;
     RECT  13.052 2.88 13.208 5.832 ;
     RECT  12.805 6.816 13.208 7.992 ;
     RECT  12.437 9.072 13.208 9.096 ;
     RECT  11.981 10.896 13.208 15.336 ;
     RECT  13.208 1.728 13.504 15.336 ;
     RECT  13.504 2.832 13.673 4.728 ;
     RECT  13.504 10.896 13.715 11.448 ;
     RECT  13.715 10.896 13.763 10.92 ;
     RECT  13.504 1.728 13.817 1.752 ;
     RECT  13.504 7.344 13.859 7.368 ;
     RECT  13.504 8.496 13.969 8.52 ;
     RECT  13.504 13.68 14.195 15.336 ;
     RECT  13.673 2.832 14.249 4.248 ;
     RECT  14.195 14.256 14.293 15.336 ;
     RECT  13.091 17.088 14.321 17.256 ;
     RECT  14.249 2.832 14.329 4.008 ;
     RECT  14.329 3.408 14.393 4.008 ;
     RECT  13.504 6.24 14.501 6.264 ;
     RECT  14.293 14.304 14.531 15.336 ;
     RECT  14.393 3.408 14.537 3.432 ;
     RECT  14.531 14.352 14.573 15.336 ;
     RECT  14.321 17.088 14.609 17.112 ;
     RECT  14.573 14.352 14.723 14.376 ;
     RECT  14.677 5.664 14.761 5.688 ;
    LAYER M5 ;
     RECT  4.536 0.016 4.608 0.084 ;
     RECT  4.632 0.016 4.704 0.084 ;
     RECT  4.728 0.016 4.8 0.084 ;
     RECT  4.824 0.016 4.896 0.084 ;
     RECT  4.92 0.016 4.992 0.084 ;
     RECT  5.016 0.016 5.088 0.084 ;
     RECT  5.112 0.016 5.184 0.084 ;
     RECT  5.208 0.016 5.28 0.084 ;
     RECT  5.304 0.016 5.376 0.084 ;
     RECT  5.4 0.016 5.472 0.084 ;
     RECT  5.496 0.016 5.568 0.084 ;
     RECT  5.592 0.016 5.664 0.084 ;
     RECT  5.688 0.016 5.76 0.084 ;
     RECT  5.784 0.016 5.856 0.084 ;
     RECT  5.88 0.016 5.952 0.084 ;
     RECT  5.976 0.016 6.048 0.084 ;
     RECT  6.072 0.016 6.144 0.084 ;
     RECT  6.168 0.016 6.24 0.084 ;
     RECT  6.264 0.016 6.336 0.084 ;
     RECT  6.36 0.016 6.432 0.084 ;
     RECT  6.456 0.016 6.528 0.084 ;
     RECT  6.552 0.016 6.624 0.084 ;
     RECT  6.648 0.016 6.72 0.084 ;
     RECT  6.744 0.016 6.816 0.084 ;
     RECT  6.84 0.016 6.912 0.084 ;
     RECT  6.936 0.016 7.008 0.084 ;
     RECT  7.032 0.016 7.104 0.084 ;
     RECT  7.128 0.016 7.2 0.084 ;
     RECT  7.224 0.016 7.296 0.084 ;
     RECT  7.32 0.016 7.392 0.084 ;
     RECT  7.416 0.016 7.488 0.084 ;
     RECT  7.512 0.016 7.584 0.084 ;
     RECT  7.608 0.016 7.68 0.084 ;
     RECT  7.704 0.016 7.776 0.084 ;
     RECT  7.8 0.016 7.872 0.084 ;
     RECT  7.896 0.016 7.968 0.084 ;
     RECT  7.992 0.016 8.064 0.084 ;
     RECT  8.088 0.016 8.16 0.084 ;
     RECT  8.184 0.016 8.256 0.084 ;
     RECT  8.28 0.016 8.352 0.084 ;
     RECT  8.376 0.016 8.448 0.084 ;
     RECT  8.472 0.016 8.544 0.084 ;
     RECT  8.568 0.016 8.64 0.084 ;
     RECT  8.664 0.016 8.736 0.084 ;
     RECT  8.76 0.016 8.832 0.084 ;
     RECT  8.856 0.016 8.928 0.084 ;
     RECT  8.952 0.016 9.024 0.084 ;
     RECT  9.048 0.016 9.12 0.084 ;
     RECT  9.144 0.016 9.216 0.084 ;
     RECT  9.24 0.016 9.312 0.084 ;
     RECT  9.336 0.016 9.408 0.084 ;
     RECT  9.432 0.016 9.504 0.084 ;
     RECT  9.528 0.016 9.6 0.084 ;
     RECT  9.624 0.016 9.696 0.084 ;
     RECT  9.72 0.016 9.792 0.084 ;
     RECT  9.816 0.016 9.888 0.084 ;
     RECT  9.912 0.016 9.984 0.084 ;
     RECT  10.008 0.016 10.08 0.084 ;
     RECT  10.104 0.016 10.176 0.084 ;
     RECT  10.2 0.016 10.272 0.084 ;
     RECT  10.296 0.016 10.368 0.084 ;
     RECT  10.392 0.016 10.464 0.084 ;
     RECT  10.488 0.016 10.56 0.084 ;
     RECT  10.584 0.016 10.656 0.084 ;
     RECT  10.68 0.016 10.752 0.084 ;
     RECT  10.776 0.016 10.848 0.084 ;
     RECT  10.872 0.016 10.944 0.084 ;
     RECT  10.968 0.016 11.04 0.084 ;
     RECT  11.064 0.016 11.136 0.084 ;
     RECT  11.16 0.016 11.232 0.084 ;
     RECT  11.256 0.016 11.328 0.084 ;
     RECT  11.352 0.016 11.424 0.084 ;
     RECT  11.448 0.016 11.52 0.084 ;
     RECT  11.544 0.016 11.616 0.084 ;
     RECT  11.64 0.016 11.712 0.084 ;
     RECT  11.736 0.016 11.808 0.084 ;
     RECT  11.832 0.016 11.904 0.084 ;
     RECT  11.928 0.016 12 0.084 ;
     RECT  12.024 0.016 12.096 0.084 ;
     RECT  12.12 0.016 12.192 0.084 ;
     RECT  12.216 0.016 12.288 0.084 ;
     RECT  12.312 0.016 12.384 0.084 ;
     RECT  12.408 0.016 12.48 0.084 ;
     RECT  12.504 0.016 12.576 0.084 ;
     RECT  12.6 0.016 12.672 0.084 ;
     RECT  12.696 0.016 12.768 0.084 ;
     RECT  4.512 0.084 12.792 2.137 ;
     RECT  2.4 2.137 2.52 2.151 ;
     RECT  4.512 2.137 13.32 2.151 ;
     RECT  4.512 2.151 13.512 2.821 ;
     RECT  4.512 2.821 14.28 2.963 ;
     RECT  7.296 2.963 14.28 3.397 ;
     RECT  7.296 3.397 14.52 3.443 ;
     RECT  7.392 3.443 14.52 3.539 ;
     RECT  7.632 3.539 14.52 3.635 ;
     RECT  7.68 3.635 9.144 3.875 ;
     RECT  10.272 3.635 14.52 4.019 ;
     RECT  7.8 3.875 9.144 4.067 ;
     RECT  4.512 2.963 6.264 5.605 ;
     RECT  12.528 4.019 14.52 5.653 ;
     RECT  7.8 4.067 8.52 6.085 ;
     RECT  3.888 5.605 6.264 6.229 ;
     RECT  7.68 6.085 8.52 6.229 ;
     RECT  3.888 6.229 8.52 6.659 ;
     RECT  10.5 4.019 11.4 6.805 ;
     RECT  3.888 6.659 8.112 6.899 ;
     RECT  9.504 6.805 11.4 7.381 ;
     RECT  12.528 5.653 14.712 7.381 ;
     RECT  4.368 6.899 8.112 10.837 ;
     RECT  9.264 7.381 14.712 10.837 ;
     RECT  4.368 10.837 14.712 14.387 ;
     RECT  4.368 14.387 14.472 14.435 ;
     RECT  4.368 14.435 13.944 14.867 ;
     RECT  4.368 14.867 13.752 15.059 ;
     RECT  2.4 2.151 2.712 15.129 ;
     RECT  4.368 15.059 13.512 15.129 ;
     RECT  2.4 15.129 2.52 15.143 ;
     RECT  4.368 15.129 13.32 15.143 ;
     RECT  4.368 15.143 13.08 16.547 ;
     RECT  4.368 16.547 12.984 17.123 ;
     RECT  4.512 17.123 12.984 17.171 ;
     RECT  4.512 17.171 12.792 17.196 ;
     RECT  4.536 17.196 4.608 17.232 ;
     RECT  4.632 17.196 4.704 17.232 ;
     RECT  4.728 17.196 4.8 17.232 ;
     RECT  4.824 17.196 4.896 17.232 ;
     RECT  4.92 17.196 4.992 17.232 ;
     RECT  5.016 17.196 5.088 17.232 ;
     RECT  5.112 17.196 5.184 17.232 ;
     RECT  5.208 17.196 5.28 17.232 ;
     RECT  5.304 17.196 5.376 17.232 ;
     RECT  5.4 17.196 5.472 17.232 ;
     RECT  5.496 17.196 5.568 17.232 ;
     RECT  5.592 17.196 5.664 17.232 ;
     RECT  5.688 17.196 5.76 17.232 ;
     RECT  5.784 17.196 5.856 17.232 ;
     RECT  5.88 17.196 5.952 17.232 ;
     RECT  5.976 17.196 6.048 17.232 ;
     RECT  6.072 17.196 6.144 17.232 ;
     RECT  6.168 17.196 6.24 17.232 ;
     RECT  6.264 17.196 6.336 17.232 ;
     RECT  6.36 17.196 6.432 17.232 ;
     RECT  6.456 17.196 6.528 17.232 ;
     RECT  6.552 17.196 6.624 17.232 ;
     RECT  6.648 17.196 6.72 17.232 ;
     RECT  6.744 17.196 6.816 17.232 ;
     RECT  6.84 17.196 6.912 17.232 ;
     RECT  6.936 17.196 7.008 17.232 ;
     RECT  7.032 17.196 7.104 17.232 ;
     RECT  7.128 17.196 7.2 17.232 ;
     RECT  7.224 17.196 7.296 17.232 ;
     RECT  7.32 17.196 7.392 17.232 ;
     RECT  7.416 17.196 7.488 17.232 ;
     RECT  7.512 17.196 7.584 17.232 ;
     RECT  7.608 17.196 7.68 17.232 ;
     RECT  7.704 17.196 7.776 17.232 ;
     RECT  7.8 17.196 7.872 17.232 ;
     RECT  7.896 17.196 7.968 17.232 ;
     RECT  7.992 17.196 8.064 17.232 ;
     RECT  8.088 17.196 8.16 17.232 ;
     RECT  8.184 17.196 8.256 17.232 ;
     RECT  8.28 17.196 8.352 17.232 ;
     RECT  8.376 17.196 8.448 17.232 ;
     RECT  8.472 17.196 8.544 17.232 ;
     RECT  8.568 17.196 8.64 17.232 ;
     RECT  8.664 17.196 8.736 17.232 ;
     RECT  8.76 17.196 8.832 17.232 ;
     RECT  8.856 17.196 8.928 17.232 ;
     RECT  8.952 17.196 9.024 17.232 ;
     RECT  9.048 17.196 9.12 17.232 ;
     RECT  9.144 17.196 9.216 17.232 ;
     RECT  9.24 17.196 9.312 17.232 ;
     RECT  9.336 17.196 9.408 17.232 ;
     RECT  9.432 17.196 9.504 17.232 ;
     RECT  9.528 17.196 9.6 17.232 ;
     RECT  9.624 17.196 9.696 17.232 ;
     RECT  9.72 17.196 9.792 17.232 ;
     RECT  9.816 17.196 9.888 17.232 ;
     RECT  9.912 17.196 9.984 17.232 ;
     RECT  10.008 17.196 10.08 17.232 ;
     RECT  10.104 17.196 10.176 17.232 ;
     RECT  10.2 17.196 10.272 17.232 ;
     RECT  10.296 17.196 10.368 17.232 ;
     RECT  10.392 17.196 10.464 17.232 ;
     RECT  10.488 17.196 10.56 17.232 ;
     RECT  10.584 17.196 10.656 17.232 ;
     RECT  10.68 17.196 10.752 17.232 ;
     RECT  10.776 17.196 10.848 17.232 ;
     RECT  10.872 17.196 10.944 17.232 ;
     RECT  10.968 17.196 11.04 17.232 ;
     RECT  11.064 17.196 11.136 17.232 ;
     RECT  11.16 17.196 11.232 17.232 ;
     RECT  11.256 17.196 11.328 17.232 ;
     RECT  11.352 17.196 11.424 17.232 ;
     RECT  11.448 17.196 11.52 17.232 ;
     RECT  11.544 17.196 11.616 17.232 ;
     RECT  11.64 17.196 11.712 17.232 ;
     RECT  11.736 17.196 11.808 17.232 ;
     RECT  11.832 17.196 11.904 17.232 ;
     RECT  11.928 17.196 12 17.232 ;
     RECT  12.024 17.196 12.096 17.232 ;
     RECT  12.12 17.196 12.192 17.232 ;
     RECT  12.216 17.196 12.288 17.232 ;
     RECT  12.312 17.196 12.384 17.232 ;
     RECT  12.408 17.196 12.48 17.232 ;
     RECT  12.504 17.196 12.576 17.232 ;
     RECT  12.6 17.196 12.672 17.232 ;
     RECT  12.696 17.196 12.768 17.232 ;
     RECT  6.264 2.963 7.296 3.443 ;
     RECT  6.264 3.443 7.392 3.539 ;
     RECT  6.264 3.539 7.632 3.635 ;
     RECT  6.264 3.635 7.68 3.875 ;
     RECT  9.144 3.635 10.272 4.019 ;
     RECT  9.144 4.019 10.5 4.067 ;
     RECT  11.4 4.019 12.528 7.381 ;
     RECT  2.712 5.605 3.888 6.899 ;
     RECT  6.264 6.085 7.68 6.229 ;
     RECT  8.112 6.659 8.52 6.805 ;
     RECT  8.112 6.805 9.504 7.381 ;
     RECT  8.112 7.381 9.264 10.837 ;
  END
END dsfd_stnv_86x1
END LIBRARY
